VERSION 5.7 ;
  NOWIREEXTENSIONATPIN ON ;
  DIVIDERCHAR "/" ;
  BUSBITCHARS "[]" ;
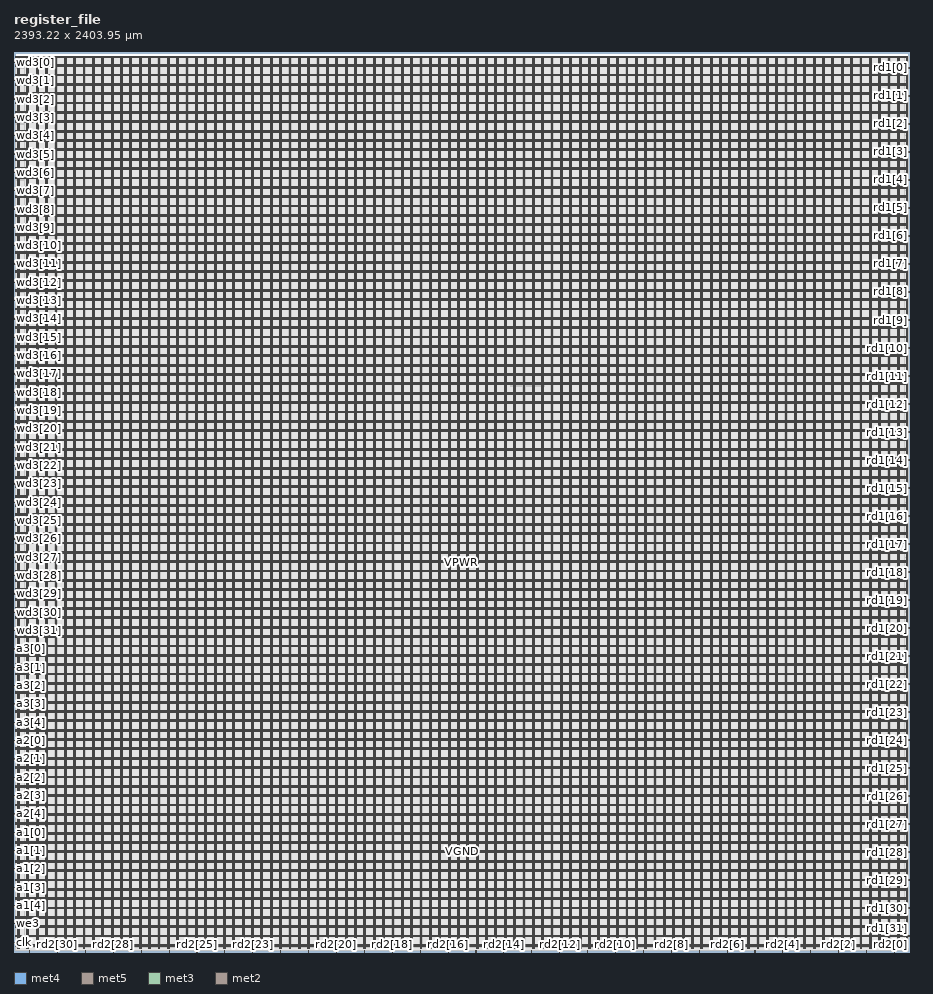
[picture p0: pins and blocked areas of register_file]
MACRO register_file
  CLASS BLOCK ;
  FOREIGN register_file ;
  ORIGIN 0.000 0.000 ;
  SIZE 2393.225 BY 2403.945 ;
  PIN VGND
    DIRECTION INOUT ;
    USE GROUND ;
    PORT
      LAYER met4 ;
        RECT 13.020 10.640 14.620 2391.120 ;
    END
    PORT
      LAYER met4 ;
        RECT 38.020 10.640 39.620 2391.120 ;
    END
    PORT
      LAYER met4 ;
        RECT 63.020 10.640 64.620 2391.120 ;
    END
    PORT
      LAYER met4 ;
        RECT 88.020 10.640 89.620 2391.120 ;
    END
    PORT
      LAYER met4 ;
        RECT 113.020 10.640 114.620 2391.120 ;
    END
    PORT
      LAYER met4 ;
        RECT 138.020 10.640 139.620 2391.120 ;
    END
    PORT
      LAYER met4 ;
        RECT 163.020 10.640 164.620 2391.120 ;
    END
    PORT
      LAYER met4 ;
        RECT 188.020 10.640 189.620 2391.120 ;
    END
    PORT
      LAYER met4 ;
        RECT 213.020 10.640 214.620 2391.120 ;
    END
    PORT
      LAYER met4 ;
        RECT 238.020 10.640 239.620 2391.120 ;
    END
    PORT
      LAYER met4 ;
        RECT 263.020 10.640 264.620 2391.120 ;
    END
    PORT
      LAYER met4 ;
        RECT 288.020 10.640 289.620 2391.120 ;
    END
    PORT
      LAYER met4 ;
        RECT 313.020 10.640 314.620 2391.120 ;
    END
    PORT
      LAYER met4 ;
        RECT 338.020 10.640 339.620 2391.120 ;
    END
    PORT
      LAYER met4 ;
        RECT 363.020 10.640 364.620 2391.120 ;
    END
    PORT
      LAYER met4 ;
        RECT 388.020 10.640 389.620 2391.120 ;
    END
    PORT
      LAYER met4 ;
        RECT 413.020 10.640 414.620 2391.120 ;
    END
    PORT
      LAYER met4 ;
        RECT 438.020 10.640 439.620 2391.120 ;
    END
    PORT
      LAYER met4 ;
        RECT 463.020 10.640 464.620 2391.120 ;
    END
    PORT
      LAYER met4 ;
        RECT 488.020 10.640 489.620 2391.120 ;
    END
    PORT
      LAYER met4 ;
        RECT 513.020 10.640 514.620 2391.120 ;
    END
    PORT
      LAYER met4 ;
        RECT 538.020 10.640 539.620 2391.120 ;
    END
    PORT
      LAYER met4 ;
        RECT 563.020 10.640 564.620 2391.120 ;
    END
    PORT
      LAYER met4 ;
        RECT 588.020 10.640 589.620 2391.120 ;
    END
    PORT
      LAYER met4 ;
        RECT 613.020 10.640 614.620 2391.120 ;
    END
    PORT
      LAYER met4 ;
        RECT 638.020 10.640 639.620 2391.120 ;
    END
    PORT
      LAYER met4 ;
        RECT 663.020 10.640 664.620 2391.120 ;
    END
    PORT
      LAYER met4 ;
        RECT 688.020 10.640 689.620 2391.120 ;
    END
    PORT
      LAYER met4 ;
        RECT 713.020 10.640 714.620 2391.120 ;
    END
    PORT
      LAYER met4 ;
        RECT 738.020 10.640 739.620 2391.120 ;
    END
    PORT
      LAYER met4 ;
        RECT 763.020 10.640 764.620 2391.120 ;
    END
    PORT
      LAYER met4 ;
        RECT 788.020 10.640 789.620 2391.120 ;
    END
    PORT
      LAYER met4 ;
        RECT 813.020 10.640 814.620 2391.120 ;
    END
    PORT
      LAYER met4 ;
        RECT 838.020 10.640 839.620 2391.120 ;
    END
    PORT
      LAYER met4 ;
        RECT 863.020 10.640 864.620 2391.120 ;
    END
    PORT
      LAYER met4 ;
        RECT 888.020 10.640 889.620 2391.120 ;
    END
    PORT
      LAYER met4 ;
        RECT 913.020 10.640 914.620 2391.120 ;
    END
    PORT
      LAYER met4 ;
        RECT 938.020 10.640 939.620 2391.120 ;
    END
    PORT
      LAYER met4 ;
        RECT 963.020 10.640 964.620 2391.120 ;
    END
    PORT
      LAYER met4 ;
        RECT 988.020 10.640 989.620 2391.120 ;
    END
    PORT
      LAYER met4 ;
        RECT 1013.020 10.640 1014.620 2391.120 ;
    END
    PORT
      LAYER met4 ;
        RECT 1038.020 10.640 1039.620 2391.120 ;
    END
    PORT
      LAYER met4 ;
        RECT 1063.020 10.640 1064.620 2391.120 ;
    END
    PORT
      LAYER met4 ;
        RECT 1088.020 10.640 1089.620 2391.120 ;
    END
    PORT
      LAYER met4 ;
        RECT 1113.020 10.640 1114.620 2391.120 ;
    END
    PORT
      LAYER met4 ;
        RECT 1138.020 10.640 1139.620 2391.120 ;
    END
    PORT
      LAYER met4 ;
        RECT 1163.020 10.640 1164.620 2391.120 ;
    END
    PORT
      LAYER met4 ;
        RECT 1188.020 10.640 1189.620 2391.120 ;
    END
    PORT
      LAYER met4 ;
        RECT 1213.020 10.640 1214.620 2391.120 ;
    END
    PORT
      LAYER met4 ;
        RECT 1238.020 10.640 1239.620 2391.120 ;
    END
    PORT
      LAYER met4 ;
        RECT 1263.020 10.640 1264.620 2391.120 ;
    END
    PORT
      LAYER met4 ;
        RECT 1288.020 10.640 1289.620 2391.120 ;
    END
    PORT
      LAYER met4 ;
        RECT 1313.020 10.640 1314.620 2391.120 ;
    END
    PORT
      LAYER met4 ;
        RECT 1338.020 10.640 1339.620 2391.120 ;
    END
    PORT
      LAYER met4 ;
        RECT 1363.020 10.640 1364.620 2391.120 ;
    END
    PORT
      LAYER met4 ;
        RECT 1388.020 10.640 1389.620 2391.120 ;
    END
    PORT
      LAYER met4 ;
        RECT 1413.020 10.640 1414.620 2391.120 ;
    END
    PORT
      LAYER met4 ;
        RECT 1438.020 10.640 1439.620 2391.120 ;
    END
    PORT
      LAYER met4 ;
        RECT 1463.020 10.640 1464.620 2391.120 ;
    END
    PORT
      LAYER met4 ;
        RECT 1488.020 10.640 1489.620 2391.120 ;
    END
    PORT
      LAYER met4 ;
        RECT 1513.020 10.640 1514.620 2391.120 ;
    END
    PORT
      LAYER met4 ;
        RECT 1538.020 10.640 1539.620 2391.120 ;
    END
    PORT
      LAYER met4 ;
        RECT 1563.020 10.640 1564.620 2391.120 ;
    END
    PORT
      LAYER met4 ;
        RECT 1588.020 10.640 1589.620 2391.120 ;
    END
    PORT
      LAYER met4 ;
        RECT 1613.020 10.640 1614.620 2391.120 ;
    END
    PORT
      LAYER met4 ;
        RECT 1638.020 10.640 1639.620 2391.120 ;
    END
    PORT
      LAYER met4 ;
        RECT 1663.020 10.640 1664.620 2391.120 ;
    END
    PORT
      LAYER met4 ;
        RECT 1688.020 10.640 1689.620 2391.120 ;
    END
    PORT
      LAYER met4 ;
        RECT 1713.020 10.640 1714.620 2391.120 ;
    END
    PORT
      LAYER met4 ;
        RECT 1738.020 10.640 1739.620 2391.120 ;
    END
    PORT
      LAYER met4 ;
        RECT 1763.020 10.640 1764.620 2391.120 ;
    END
    PORT
      LAYER met4 ;
        RECT 1788.020 10.640 1789.620 2391.120 ;
    END
    PORT
      LAYER met4 ;
        RECT 1813.020 10.640 1814.620 2391.120 ;
    END
    PORT
      LAYER met4 ;
        RECT 1838.020 10.640 1839.620 2391.120 ;
    END
    PORT
      LAYER met4 ;
        RECT 1863.020 10.640 1864.620 2391.120 ;
    END
    PORT
      LAYER met4 ;
        RECT 1888.020 10.640 1889.620 2391.120 ;
    END
    PORT
      LAYER met4 ;
        RECT 1913.020 10.640 1914.620 2391.120 ;
    END
    PORT
      LAYER met4 ;
        RECT 1938.020 10.640 1939.620 2391.120 ;
    END
    PORT
      LAYER met4 ;
        RECT 1963.020 10.640 1964.620 2391.120 ;
    END
    PORT
      LAYER met4 ;
        RECT 1988.020 10.640 1989.620 2391.120 ;
    END
    PORT
      LAYER met4 ;
        RECT 2013.020 10.640 2014.620 2391.120 ;
    END
    PORT
      LAYER met4 ;
        RECT 2038.020 10.640 2039.620 2391.120 ;
    END
    PORT
      LAYER met4 ;
        RECT 2063.020 10.640 2064.620 2391.120 ;
    END
    PORT
      LAYER met4 ;
        RECT 2088.020 10.640 2089.620 2391.120 ;
    END
    PORT
      LAYER met4 ;
        RECT 2113.020 10.640 2114.620 2391.120 ;
    END
    PORT
      LAYER met4 ;
        RECT 2138.020 10.640 2139.620 2391.120 ;
    END
    PORT
      LAYER met4 ;
        RECT 2163.020 10.640 2164.620 2391.120 ;
    END
    PORT
      LAYER met4 ;
        RECT 2188.020 10.640 2189.620 2391.120 ;
    END
    PORT
      LAYER met4 ;
        RECT 2213.020 10.640 2214.620 2391.120 ;
    END
    PORT
      LAYER met4 ;
        RECT 2238.020 10.640 2239.620 2391.120 ;
    END
    PORT
      LAYER met4 ;
        RECT 2263.020 10.640 2264.620 2391.120 ;
    END
    PORT
      LAYER met4 ;
        RECT 2288.020 10.640 2289.620 2391.120 ;
    END
    PORT
      LAYER met4 ;
        RECT 2313.020 10.640 2314.620 2391.120 ;
    END
    PORT
      LAYER met4 ;
        RECT 2338.020 10.640 2339.620 2391.120 ;
    END
    PORT
      LAYER met4 ;
        RECT 2363.020 10.640 2364.620 2391.120 ;
    END
    PORT
      LAYER met5 ;
        RECT 5.280 18.380 2387.640 19.980 ;
    END
    PORT
      LAYER met5 ;
        RECT 5.280 43.380 2387.640 44.980 ;
    END
    PORT
      LAYER met5 ;
        RECT 5.280 68.380 2387.640 69.980 ;
    END
    PORT
      LAYER met5 ;
        RECT 5.280 93.380 2387.640 94.980 ;
    END
    PORT
      LAYER met5 ;
        RECT 5.280 118.380 2387.640 119.980 ;
    END
    PORT
      LAYER met5 ;
        RECT 5.280 143.380 2387.640 144.980 ;
    END
    PORT
      LAYER met5 ;
        RECT 5.280 168.380 2387.640 169.980 ;
    END
    PORT
      LAYER met5 ;
        RECT 5.280 193.380 2387.640 194.980 ;
    END
    PORT
      LAYER met5 ;
        RECT 5.280 218.380 2387.640 219.980 ;
    END
    PORT
      LAYER met5 ;
        RECT 5.280 243.380 2387.640 244.980 ;
    END
    PORT
      LAYER met5 ;
        RECT 5.280 268.380 2387.640 269.980 ;
    END
    PORT
      LAYER met5 ;
        RECT 5.280 293.380 2387.640 294.980 ;
    END
    PORT
      LAYER met5 ;
        RECT 5.280 318.380 2387.640 319.980 ;
    END
    PORT
      LAYER met5 ;
        RECT 5.280 343.380 2387.640 344.980 ;
    END
    PORT
      LAYER met5 ;
        RECT 5.280 368.380 2387.640 369.980 ;
    END
    PORT
      LAYER met5 ;
        RECT 5.280 393.380 2387.640 394.980 ;
    END
    PORT
      LAYER met5 ;
        RECT 5.280 418.380 2387.640 419.980 ;
    END
    PORT
      LAYER met5 ;
        RECT 5.280 443.380 2387.640 444.980 ;
    END
    PORT
      LAYER met5 ;
        RECT 5.280 468.380 2387.640 469.980 ;
    END
    PORT
      LAYER met5 ;
        RECT 5.280 493.380 2387.640 494.980 ;
    END
    PORT
      LAYER met5 ;
        RECT 5.280 518.380 2387.640 519.980 ;
    END
    PORT
      LAYER met5 ;
        RECT 5.280 543.380 2387.640 544.980 ;
    END
    PORT
      LAYER met5 ;
        RECT 5.280 568.380 2387.640 569.980 ;
    END
    PORT
      LAYER met5 ;
        RECT 5.280 593.380 2387.640 594.980 ;
    END
    PORT
      LAYER met5 ;
        RECT 5.280 618.380 2387.640 619.980 ;
    END
    PORT
      LAYER met5 ;
        RECT 5.280 643.380 2387.640 644.980 ;
    END
    PORT
      LAYER met5 ;
        RECT 5.280 668.380 2387.640 669.980 ;
    END
    PORT
      LAYER met5 ;
        RECT 5.280 693.380 2387.640 694.980 ;
    END
    PORT
      LAYER met5 ;
        RECT 5.280 718.380 2387.640 719.980 ;
    END
    PORT
      LAYER met5 ;
        RECT 5.280 743.380 2387.640 744.980 ;
    END
    PORT
      LAYER met5 ;
        RECT 5.280 768.380 2387.640 769.980 ;
    END
    PORT
      LAYER met5 ;
        RECT 5.280 793.380 2387.640 794.980 ;
    END
    PORT
      LAYER met5 ;
        RECT 5.280 818.380 2387.640 819.980 ;
    END
    PORT
      LAYER met5 ;
        RECT 5.280 843.380 2387.640 844.980 ;
    END
    PORT
      LAYER met5 ;
        RECT 5.280 868.380 2387.640 869.980 ;
    END
    PORT
      LAYER met5 ;
        RECT 5.280 893.380 2387.640 894.980 ;
    END
    PORT
      LAYER met5 ;
        RECT 5.280 918.380 2387.640 919.980 ;
    END
    PORT
      LAYER met5 ;
        RECT 5.280 943.380 2387.640 944.980 ;
    END
    PORT
      LAYER met5 ;
        RECT 5.280 968.380 2387.640 969.980 ;
    END
    PORT
      LAYER met5 ;
        RECT 5.280 993.380 2387.640 994.980 ;
    END
    PORT
      LAYER met5 ;
        RECT 5.280 1018.380 2387.640 1019.980 ;
    END
    PORT
      LAYER met5 ;
        RECT 5.280 1043.380 2387.640 1044.980 ;
    END
    PORT
      LAYER met5 ;
        RECT 5.280 1068.380 2387.640 1069.980 ;
    END
    PORT
      LAYER met5 ;
        RECT 5.280 1093.380 2387.640 1094.980 ;
    END
    PORT
      LAYER met5 ;
        RECT 5.280 1118.380 2387.640 1119.980 ;
    END
    PORT
      LAYER met5 ;
        RECT 5.280 1143.380 2387.640 1144.980 ;
    END
    PORT
      LAYER met5 ;
        RECT 5.280 1168.380 2387.640 1169.980 ;
    END
    PORT
      LAYER met5 ;
        RECT 5.280 1193.380 2387.640 1194.980 ;
    END
    PORT
      LAYER met5 ;
        RECT 5.280 1218.380 2387.640 1219.980 ;
    END
    PORT
      LAYER met5 ;
        RECT 5.280 1243.380 2387.640 1244.980 ;
    END
    PORT
      LAYER met5 ;
        RECT 5.280 1268.380 2387.640 1269.980 ;
    END
    PORT
      LAYER met5 ;
        RECT 5.280 1293.380 2387.640 1294.980 ;
    END
    PORT
      LAYER met5 ;
        RECT 5.280 1318.380 2387.640 1319.980 ;
    END
    PORT
      LAYER met5 ;
        RECT 5.280 1343.380 2387.640 1344.980 ;
    END
    PORT
      LAYER met5 ;
        RECT 5.280 1368.380 2387.640 1369.980 ;
    END
    PORT
      LAYER met5 ;
        RECT 5.280 1393.380 2387.640 1394.980 ;
    END
    PORT
      LAYER met5 ;
        RECT 5.280 1418.380 2387.640 1419.980 ;
    END
    PORT
      LAYER met5 ;
        RECT 5.280 1443.380 2387.640 1444.980 ;
    END
    PORT
      LAYER met5 ;
        RECT 5.280 1468.380 2387.640 1469.980 ;
    END
    PORT
      LAYER met5 ;
        RECT 5.280 1493.380 2387.640 1494.980 ;
    END
    PORT
      LAYER met5 ;
        RECT 5.280 1518.380 2387.640 1519.980 ;
    END
    PORT
      LAYER met5 ;
        RECT 5.280 1543.380 2387.640 1544.980 ;
    END
    PORT
      LAYER met5 ;
        RECT 5.280 1568.380 2387.640 1569.980 ;
    END
    PORT
      LAYER met5 ;
        RECT 5.280 1593.380 2387.640 1594.980 ;
    END
    PORT
      LAYER met5 ;
        RECT 5.280 1618.380 2387.640 1619.980 ;
    END
    PORT
      LAYER met5 ;
        RECT 5.280 1643.380 2387.640 1644.980 ;
    END
    PORT
      LAYER met5 ;
        RECT 5.280 1668.380 2387.640 1669.980 ;
    END
    PORT
      LAYER met5 ;
        RECT 5.280 1693.380 2387.640 1694.980 ;
    END
    PORT
      LAYER met5 ;
        RECT 5.280 1718.380 2387.640 1719.980 ;
    END
    PORT
      LAYER met5 ;
        RECT 5.280 1743.380 2387.640 1744.980 ;
    END
    PORT
      LAYER met5 ;
        RECT 5.280 1768.380 2387.640 1769.980 ;
    END
    PORT
      LAYER met5 ;
        RECT 5.280 1793.380 2387.640 1794.980 ;
    END
    PORT
      LAYER met5 ;
        RECT 5.280 1818.380 2387.640 1819.980 ;
    END
    PORT
      LAYER met5 ;
        RECT 5.280 1843.380 2387.640 1844.980 ;
    END
    PORT
      LAYER met5 ;
        RECT 5.280 1868.380 2387.640 1869.980 ;
    END
    PORT
      LAYER met5 ;
        RECT 5.280 1893.380 2387.640 1894.980 ;
    END
    PORT
      LAYER met5 ;
        RECT 5.280 1918.380 2387.640 1919.980 ;
    END
    PORT
      LAYER met5 ;
        RECT 5.280 1943.380 2387.640 1944.980 ;
    END
    PORT
      LAYER met5 ;
        RECT 5.280 1968.380 2387.640 1969.980 ;
    END
    PORT
      LAYER met5 ;
        RECT 5.280 1993.380 2387.640 1994.980 ;
    END
    PORT
      LAYER met5 ;
        RECT 5.280 2018.380 2387.640 2019.980 ;
    END
    PORT
      LAYER met5 ;
        RECT 5.280 2043.380 2387.640 2044.980 ;
    END
    PORT
      LAYER met5 ;
        RECT 5.280 2068.380 2387.640 2069.980 ;
    END
    PORT
      LAYER met5 ;
        RECT 5.280 2093.380 2387.640 2094.980 ;
    END
    PORT
      LAYER met5 ;
        RECT 5.280 2118.380 2387.640 2119.980 ;
    END
    PORT
      LAYER met5 ;
        RECT 5.280 2143.380 2387.640 2144.980 ;
    END
    PORT
      LAYER met5 ;
        RECT 5.280 2168.380 2387.640 2169.980 ;
    END
    PORT
      LAYER met5 ;
        RECT 5.280 2193.380 2387.640 2194.980 ;
    END
    PORT
      LAYER met5 ;
        RECT 5.280 2218.380 2387.640 2219.980 ;
    END
    PORT
      LAYER met5 ;
        RECT 5.280 2243.380 2387.640 2244.980 ;
    END
    PORT
      LAYER met5 ;
        RECT 5.280 2268.380 2387.640 2269.980 ;
    END
    PORT
      LAYER met5 ;
        RECT 5.280 2293.380 2387.640 2294.980 ;
    END
    PORT
      LAYER met5 ;
        RECT 5.280 2318.380 2387.640 2319.980 ;
    END
    PORT
      LAYER met5 ;
        RECT 5.280 2343.380 2387.640 2344.980 ;
    END
    PORT
      LAYER met5 ;
        RECT 5.280 2368.380 2387.640 2369.980 ;
    END
  END VGND
  PIN VPWR
    DIRECTION INOUT ;
    USE POWER ;
    PORT
      LAYER met4 ;
        RECT 9.720 10.640 11.320 2391.680 ;
    END
    PORT
      LAYER met4 ;
        RECT 34.720 10.640 36.320 2391.680 ;
    END
    PORT
      LAYER met4 ;
        RECT 59.720 10.640 61.320 2391.680 ;
    END
    PORT
      LAYER met4 ;
        RECT 84.720 10.640 86.320 2391.680 ;
    END
    PORT
      LAYER met4 ;
        RECT 109.720 10.640 111.320 2391.680 ;
    END
    PORT
      LAYER met4 ;
        RECT 134.720 10.640 136.320 2391.680 ;
    END
    PORT
      LAYER met4 ;
        RECT 159.720 10.640 161.320 2391.680 ;
    END
    PORT
      LAYER met4 ;
        RECT 184.720 10.640 186.320 2391.680 ;
    END
    PORT
      LAYER met4 ;
        RECT 209.720 10.640 211.320 2391.680 ;
    END
    PORT
      LAYER met4 ;
        RECT 234.720 10.640 236.320 2391.680 ;
    END
    PORT
      LAYER met4 ;
        RECT 259.720 10.640 261.320 2391.680 ;
    END
    PORT
      LAYER met4 ;
        RECT 284.720 10.640 286.320 2391.680 ;
    END
    PORT
      LAYER met4 ;
        RECT 309.720 10.640 311.320 2391.680 ;
    END
    PORT
      LAYER met4 ;
        RECT 334.720 10.640 336.320 2391.680 ;
    END
    PORT
      LAYER met4 ;
        RECT 359.720 10.640 361.320 2391.680 ;
    END
    PORT
      LAYER met4 ;
        RECT 384.720 10.640 386.320 2391.680 ;
    END
    PORT
      LAYER met4 ;
        RECT 409.720 10.640 411.320 2391.680 ;
    END
    PORT
      LAYER met4 ;
        RECT 434.720 10.640 436.320 2391.680 ;
    END
    PORT
      LAYER met4 ;
        RECT 459.720 10.640 461.320 2391.680 ;
    END
    PORT
      LAYER met4 ;
        RECT 484.720 10.640 486.320 2391.680 ;
    END
    PORT
      LAYER met4 ;
        RECT 509.720 10.640 511.320 2391.680 ;
    END
    PORT
      LAYER met4 ;
        RECT 534.720 10.640 536.320 2391.680 ;
    END
    PORT
      LAYER met4 ;
        RECT 559.720 10.640 561.320 2391.680 ;
    END
    PORT
      LAYER met4 ;
        RECT 584.720 10.640 586.320 2391.680 ;
    END
    PORT
      LAYER met4 ;
        RECT 609.720 10.640 611.320 2391.680 ;
    END
    PORT
      LAYER met4 ;
        RECT 634.720 10.640 636.320 2391.680 ;
    END
    PORT
      LAYER met4 ;
        RECT 659.720 10.640 661.320 2391.680 ;
    END
    PORT
      LAYER met4 ;
        RECT 684.720 10.640 686.320 2391.680 ;
    END
    PORT
      LAYER met4 ;
        RECT 709.720 10.640 711.320 2391.680 ;
    END
    PORT
      LAYER met4 ;
        RECT 734.720 10.640 736.320 2391.680 ;
    END
    PORT
      LAYER met4 ;
        RECT 759.720 10.640 761.320 2391.680 ;
    END
    PORT
      LAYER met4 ;
        RECT 784.720 10.640 786.320 2391.680 ;
    END
    PORT
      LAYER met4 ;
        RECT 809.720 10.640 811.320 2391.680 ;
    END
    PORT
      LAYER met4 ;
        RECT 834.720 10.640 836.320 2391.680 ;
    END
    PORT
      LAYER met4 ;
        RECT 859.720 10.640 861.320 2391.680 ;
    END
    PORT
      LAYER met4 ;
        RECT 884.720 10.640 886.320 2391.680 ;
    END
    PORT
      LAYER met4 ;
        RECT 909.720 10.640 911.320 2391.680 ;
    END
    PORT
      LAYER met4 ;
        RECT 934.720 10.640 936.320 2391.680 ;
    END
    PORT
      LAYER met4 ;
        RECT 959.720 10.640 961.320 2391.680 ;
    END
    PORT
      LAYER met4 ;
        RECT 984.720 10.640 986.320 2391.680 ;
    END
    PORT
      LAYER met4 ;
        RECT 1009.720 10.640 1011.320 2391.680 ;
    END
    PORT
      LAYER met4 ;
        RECT 1034.720 10.640 1036.320 2391.680 ;
    END
    PORT
      LAYER met4 ;
        RECT 1059.720 10.640 1061.320 2391.680 ;
    END
    PORT
      LAYER met4 ;
        RECT 1084.720 10.640 1086.320 2391.680 ;
    END
    PORT
      LAYER met4 ;
        RECT 1109.720 10.640 1111.320 2391.680 ;
    END
    PORT
      LAYER met4 ;
        RECT 1134.720 10.640 1136.320 2391.680 ;
    END
    PORT
      LAYER met4 ;
        RECT 1159.720 10.640 1161.320 2391.680 ;
    END
    PORT
      LAYER met4 ;
        RECT 1184.720 10.640 1186.320 2391.680 ;
    END
    PORT
      LAYER met4 ;
        RECT 1209.720 10.640 1211.320 2391.680 ;
    END
    PORT
      LAYER met4 ;
        RECT 1234.720 10.640 1236.320 2391.680 ;
    END
    PORT
      LAYER met4 ;
        RECT 1259.720 10.640 1261.320 2391.680 ;
    END
    PORT
      LAYER met4 ;
        RECT 1284.720 10.640 1286.320 2391.680 ;
    END
    PORT
      LAYER met4 ;
        RECT 1309.720 10.640 1311.320 2391.680 ;
    END
    PORT
      LAYER met4 ;
        RECT 1334.720 10.640 1336.320 2391.680 ;
    END
    PORT
      LAYER met4 ;
        RECT 1359.720 10.640 1361.320 2391.680 ;
    END
    PORT
      LAYER met4 ;
        RECT 1384.720 10.640 1386.320 2391.680 ;
    END
    PORT
      LAYER met4 ;
        RECT 1409.720 10.640 1411.320 2391.680 ;
    END
    PORT
      LAYER met4 ;
        RECT 1434.720 10.640 1436.320 2391.680 ;
    END
    PORT
      LAYER met4 ;
        RECT 1459.720 10.640 1461.320 2391.680 ;
    END
    PORT
      LAYER met4 ;
        RECT 1484.720 10.640 1486.320 2391.680 ;
    END
    PORT
      LAYER met4 ;
        RECT 1509.720 10.640 1511.320 2391.680 ;
    END
    PORT
      LAYER met4 ;
        RECT 1534.720 10.640 1536.320 2391.680 ;
    END
    PORT
      LAYER met4 ;
        RECT 1559.720 10.640 1561.320 2391.680 ;
    END
    PORT
      LAYER met4 ;
        RECT 1584.720 10.640 1586.320 2391.680 ;
    END
    PORT
      LAYER met4 ;
        RECT 1609.720 10.640 1611.320 2391.680 ;
    END
    PORT
      LAYER met4 ;
        RECT 1634.720 10.640 1636.320 2391.680 ;
    END
    PORT
      LAYER met4 ;
        RECT 1659.720 10.640 1661.320 2391.680 ;
    END
    PORT
      LAYER met4 ;
        RECT 1684.720 10.640 1686.320 2391.680 ;
    END
    PORT
      LAYER met4 ;
        RECT 1709.720 10.640 1711.320 2391.680 ;
    END
    PORT
      LAYER met4 ;
        RECT 1734.720 10.640 1736.320 2391.680 ;
    END
    PORT
      LAYER met4 ;
        RECT 1759.720 10.640 1761.320 2391.680 ;
    END
    PORT
      LAYER met4 ;
        RECT 1784.720 10.640 1786.320 2391.680 ;
    END
    PORT
      LAYER met4 ;
        RECT 1809.720 10.640 1811.320 2391.680 ;
    END
    PORT
      LAYER met4 ;
        RECT 1834.720 10.640 1836.320 2391.680 ;
    END
    PORT
      LAYER met4 ;
        RECT 1859.720 10.640 1861.320 2391.680 ;
    END
    PORT
      LAYER met4 ;
        RECT 1884.720 10.640 1886.320 2391.680 ;
    END
    PORT
      LAYER met4 ;
        RECT 1909.720 10.640 1911.320 2391.680 ;
    END
    PORT
      LAYER met4 ;
        RECT 1934.720 10.640 1936.320 2391.680 ;
    END
    PORT
      LAYER met4 ;
        RECT 1959.720 10.640 1961.320 2391.680 ;
    END
    PORT
      LAYER met4 ;
        RECT 1984.720 10.640 1986.320 2391.680 ;
    END
    PORT
      LAYER met4 ;
        RECT 2009.720 10.640 2011.320 2391.680 ;
    END
    PORT
      LAYER met4 ;
        RECT 2034.720 10.640 2036.320 2391.680 ;
    END
    PORT
      LAYER met4 ;
        RECT 2059.720 10.640 2061.320 2391.680 ;
    END
    PORT
      LAYER met4 ;
        RECT 2084.720 10.640 2086.320 2391.680 ;
    END
    PORT
      LAYER met4 ;
        RECT 2109.720 10.640 2111.320 2391.680 ;
    END
    PORT
      LAYER met4 ;
        RECT 2134.720 10.640 2136.320 2391.680 ;
    END
    PORT
      LAYER met4 ;
        RECT 2159.720 10.640 2161.320 2391.680 ;
    END
    PORT
      LAYER met4 ;
        RECT 2184.720 10.640 2186.320 2391.680 ;
    END
    PORT
      LAYER met4 ;
        RECT 2209.720 10.640 2211.320 2391.680 ;
    END
    PORT
      LAYER met4 ;
        RECT 2234.720 10.640 2236.320 2391.680 ;
    END
    PORT
      LAYER met4 ;
        RECT 2259.720 10.640 2261.320 2391.680 ;
    END
    PORT
      LAYER met4 ;
        RECT 2284.720 10.640 2286.320 2391.680 ;
    END
    PORT
      LAYER met4 ;
        RECT 2309.720 10.640 2311.320 2391.680 ;
    END
    PORT
      LAYER met4 ;
        RECT 2334.720 10.640 2336.320 2391.680 ;
    END
    PORT
      LAYER met4 ;
        RECT 2359.720 10.640 2361.320 2391.680 ;
    END
    PORT
      LAYER met4 ;
        RECT 2384.720 10.640 2386.320 2391.680 ;
    END
    PORT
      LAYER met5 ;
        RECT 5.280 15.080 2387.640 16.680 ;
    END
    PORT
      LAYER met5 ;
        RECT 5.280 40.080 2387.640 41.680 ;
    END
    PORT
      LAYER met5 ;
        RECT 5.280 65.080 2387.640 66.680 ;
    END
    PORT
      LAYER met5 ;
        RECT 5.280 90.080 2387.640 91.680 ;
    END
    PORT
      LAYER met5 ;
        RECT 5.280 115.080 2387.640 116.680 ;
    END
    PORT
      LAYER met5 ;
        RECT 5.280 140.080 2387.640 141.680 ;
    END
    PORT
      LAYER met5 ;
        RECT 5.280 165.080 2387.640 166.680 ;
    END
    PORT
      LAYER met5 ;
        RECT 5.280 190.080 2387.640 191.680 ;
    END
    PORT
      LAYER met5 ;
        RECT 5.280 215.080 2387.640 216.680 ;
    END
    PORT
      LAYER met5 ;
        RECT 5.280 240.080 2387.640 241.680 ;
    END
    PORT
      LAYER met5 ;
        RECT 5.280 265.080 2387.640 266.680 ;
    END
    PORT
      LAYER met5 ;
        RECT 5.280 290.080 2387.640 291.680 ;
    END
    PORT
      LAYER met5 ;
        RECT 5.280 315.080 2387.640 316.680 ;
    END
    PORT
      LAYER met5 ;
        RECT 5.280 340.080 2387.640 341.680 ;
    END
    PORT
      LAYER met5 ;
        RECT 5.280 365.080 2387.640 366.680 ;
    END
    PORT
      LAYER met5 ;
        RECT 5.280 390.080 2387.640 391.680 ;
    END
    PORT
      LAYER met5 ;
        RECT 5.280 415.080 2387.640 416.680 ;
    END
    PORT
      LAYER met5 ;
        RECT 5.280 440.080 2387.640 441.680 ;
    END
    PORT
      LAYER met5 ;
        RECT 5.280 465.080 2387.640 466.680 ;
    END
    PORT
      LAYER met5 ;
        RECT 5.280 490.080 2387.640 491.680 ;
    END
    PORT
      LAYER met5 ;
        RECT 5.280 515.080 2387.640 516.680 ;
    END
    PORT
      LAYER met5 ;
        RECT 5.280 540.080 2387.640 541.680 ;
    END
    PORT
      LAYER met5 ;
        RECT 5.280 565.080 2387.640 566.680 ;
    END
    PORT
      LAYER met5 ;
        RECT 5.280 590.080 2387.640 591.680 ;
    END
    PORT
      LAYER met5 ;
        RECT 5.280 615.080 2387.640 616.680 ;
    END
    PORT
      LAYER met5 ;
        RECT 5.280 640.080 2387.640 641.680 ;
    END
    PORT
      LAYER met5 ;
        RECT 5.280 665.080 2387.640 666.680 ;
    END
    PORT
      LAYER met5 ;
        RECT 5.280 690.080 2387.640 691.680 ;
    END
    PORT
      LAYER met5 ;
        RECT 5.280 715.080 2387.640 716.680 ;
    END
    PORT
      LAYER met5 ;
        RECT 5.280 740.080 2387.640 741.680 ;
    END
    PORT
      LAYER met5 ;
        RECT 5.280 765.080 2387.640 766.680 ;
    END
    PORT
      LAYER met5 ;
        RECT 5.280 790.080 2387.640 791.680 ;
    END
    PORT
      LAYER met5 ;
        RECT 5.280 815.080 2387.640 816.680 ;
    END
    PORT
      LAYER met5 ;
        RECT 5.280 840.080 2387.640 841.680 ;
    END
    PORT
      LAYER met5 ;
        RECT 5.280 865.080 2387.640 866.680 ;
    END
    PORT
      LAYER met5 ;
        RECT 5.280 890.080 2387.640 891.680 ;
    END
    PORT
      LAYER met5 ;
        RECT 5.280 915.080 2387.640 916.680 ;
    END
    PORT
      LAYER met5 ;
        RECT 5.280 940.080 2387.640 941.680 ;
    END
    PORT
      LAYER met5 ;
        RECT 5.280 965.080 2387.640 966.680 ;
    END
    PORT
      LAYER met5 ;
        RECT 5.280 990.080 2387.640 991.680 ;
    END
    PORT
      LAYER met5 ;
        RECT 5.280 1015.080 2387.640 1016.680 ;
    END
    PORT
      LAYER met5 ;
        RECT 5.280 1040.080 2387.640 1041.680 ;
    END
    PORT
      LAYER met5 ;
        RECT 5.280 1065.080 2387.640 1066.680 ;
    END
    PORT
      LAYER met5 ;
        RECT 5.280 1090.080 2387.640 1091.680 ;
    END
    PORT
      LAYER met5 ;
        RECT 5.280 1115.080 2387.640 1116.680 ;
    END
    PORT
      LAYER met5 ;
        RECT 5.280 1140.080 2387.640 1141.680 ;
    END
    PORT
      LAYER met5 ;
        RECT 5.280 1165.080 2387.640 1166.680 ;
    END
    PORT
      LAYER met5 ;
        RECT 5.280 1190.080 2387.640 1191.680 ;
    END
    PORT
      LAYER met5 ;
        RECT 5.280 1215.080 2387.640 1216.680 ;
    END
    PORT
      LAYER met5 ;
        RECT 5.280 1240.080 2387.640 1241.680 ;
    END
    PORT
      LAYER met5 ;
        RECT 5.280 1265.080 2387.640 1266.680 ;
    END
    PORT
      LAYER met5 ;
        RECT 5.280 1290.080 2387.640 1291.680 ;
    END
    PORT
      LAYER met5 ;
        RECT 5.280 1315.080 2387.640 1316.680 ;
    END
    PORT
      LAYER met5 ;
        RECT 5.280 1340.080 2387.640 1341.680 ;
    END
    PORT
      LAYER met5 ;
        RECT 5.280 1365.080 2387.640 1366.680 ;
    END
    PORT
      LAYER met5 ;
        RECT 5.280 1390.080 2387.640 1391.680 ;
    END
    PORT
      LAYER met5 ;
        RECT 5.280 1415.080 2387.640 1416.680 ;
    END
    PORT
      LAYER met5 ;
        RECT 5.280 1440.080 2387.640 1441.680 ;
    END
    PORT
      LAYER met5 ;
        RECT 5.280 1465.080 2387.640 1466.680 ;
    END
    PORT
      LAYER met5 ;
        RECT 5.280 1490.080 2387.640 1491.680 ;
    END
    PORT
      LAYER met5 ;
        RECT 5.280 1515.080 2387.640 1516.680 ;
    END
    PORT
      LAYER met5 ;
        RECT 5.280 1540.080 2387.640 1541.680 ;
    END
    PORT
      LAYER met5 ;
        RECT 5.280 1565.080 2387.640 1566.680 ;
    END
    PORT
      LAYER met5 ;
        RECT 5.280 1590.080 2387.640 1591.680 ;
    END
    PORT
      LAYER met5 ;
        RECT 5.280 1615.080 2387.640 1616.680 ;
    END
    PORT
      LAYER met5 ;
        RECT 5.280 1640.080 2387.640 1641.680 ;
    END
    PORT
      LAYER met5 ;
        RECT 5.280 1665.080 2387.640 1666.680 ;
    END
    PORT
      LAYER met5 ;
        RECT 5.280 1690.080 2387.640 1691.680 ;
    END
    PORT
      LAYER met5 ;
        RECT 5.280 1715.080 2387.640 1716.680 ;
    END
    PORT
      LAYER met5 ;
        RECT 5.280 1740.080 2387.640 1741.680 ;
    END
    PORT
      LAYER met5 ;
        RECT 5.280 1765.080 2387.640 1766.680 ;
    END
    PORT
      LAYER met5 ;
        RECT 5.280 1790.080 2387.640 1791.680 ;
    END
    PORT
      LAYER met5 ;
        RECT 5.280 1815.080 2387.640 1816.680 ;
    END
    PORT
      LAYER met5 ;
        RECT 5.280 1840.080 2387.640 1841.680 ;
    END
    PORT
      LAYER met5 ;
        RECT 5.280 1865.080 2387.640 1866.680 ;
    END
    PORT
      LAYER met5 ;
        RECT 5.280 1890.080 2387.640 1891.680 ;
    END
    PORT
      LAYER met5 ;
        RECT 5.280 1915.080 2387.640 1916.680 ;
    END
    PORT
      LAYER met5 ;
        RECT 5.280 1940.080 2387.640 1941.680 ;
    END
    PORT
      LAYER met5 ;
        RECT 5.280 1965.080 2387.640 1966.680 ;
    END
    PORT
      LAYER met5 ;
        RECT 5.280 1990.080 2387.640 1991.680 ;
    END
    PORT
      LAYER met5 ;
        RECT 5.280 2015.080 2387.640 2016.680 ;
    END
    PORT
      LAYER met5 ;
        RECT 5.280 2040.080 2387.640 2041.680 ;
    END
    PORT
      LAYER met5 ;
        RECT 5.280 2065.080 2387.640 2066.680 ;
    END
    PORT
      LAYER met5 ;
        RECT 5.280 2090.080 2387.640 2091.680 ;
    END
    PORT
      LAYER met5 ;
        RECT 5.280 2115.080 2387.640 2116.680 ;
    END
    PORT
      LAYER met5 ;
        RECT 5.280 2140.080 2387.640 2141.680 ;
    END
    PORT
      LAYER met5 ;
        RECT 5.280 2165.080 2387.640 2166.680 ;
    END
    PORT
      LAYER met5 ;
        RECT 5.280 2190.080 2387.640 2191.680 ;
    END
    PORT
      LAYER met5 ;
        RECT 5.280 2215.080 2387.640 2216.680 ;
    END
    PORT
      LAYER met5 ;
        RECT 5.280 2240.080 2387.640 2241.680 ;
    END
    PORT
      LAYER met5 ;
        RECT 5.280 2265.080 2387.640 2266.680 ;
    END
    PORT
      LAYER met5 ;
        RECT 5.280 2290.080 2387.640 2291.680 ;
    END
    PORT
      LAYER met5 ;
        RECT 5.280 2315.080 2387.640 2316.680 ;
    END
    PORT
      LAYER met5 ;
        RECT 5.280 2340.080 2387.640 2341.680 ;
    END
    PORT
      LAYER met5 ;
        RECT 5.280 2365.080 2387.640 2366.680 ;
    END
    PORT
      LAYER met5 ;
        RECT 5.280 2390.080 2387.640 2391.680 ;
    END
  END VPWR
  PIN a1[0]
    DIRECTION INPUT ;
    USE SIGNAL ;
    ANTENNAGATEAREA 0.852000 ;
    ANTENNADIFFAREA 2.173500 ;
    PORT
      LAYER met3 ;
        RECT 0.000 319.640 4.000 320.240 ;
    END
  END a1[0]
  PIN a1[1]
    DIRECTION INPUT ;
    USE SIGNAL ;
    ANTENNAGATEAREA 0.990000 ;
    PORT
      LAYER met3 ;
        RECT 0.000 270.680 4.000 271.280 ;
    END
  END a1[1]
  PIN a1[2]
    DIRECTION INPUT ;
    USE SIGNAL ;
    ANTENNAGATEAREA 0.852000 ;
    PORT
      LAYER met3 ;
        RECT 0.000 221.720 4.000 222.320 ;
    END
  END a1[2]
  PIN a1[3]
    DIRECTION INPUT ;
    USE SIGNAL ;
    ANTENNAGATEAREA 0.990000 ;
    PORT
      LAYER met3 ;
        RECT 0.000 172.760 4.000 173.360 ;
    END
  END a1[3]
  PIN a1[4]
    DIRECTION INPUT ;
    USE SIGNAL ;
    ANTENNAGATEAREA 0.990000 ;
    PORT
      LAYER met3 ;
        RECT 0.000 123.800 4.000 124.400 ;
    END
  END a1[4]
  PIN a2[0]
    DIRECTION INPUT ;
    USE SIGNAL ;
    ANTENNAGATEAREA 0.742500 ;
    ANTENNADIFFAREA 0.434700 ;
    PORT
      LAYER met3 ;
        RECT 0.000 564.440 4.000 565.040 ;
    END
  END a2[0]
  PIN a2[1]
    DIRECTION INPUT ;
    USE SIGNAL ;
    ANTENNAGATEAREA 0.990000 ;
    PORT
      LAYER met3 ;
        RECT 0.000 515.480 4.000 516.080 ;
    END
  END a2[1]
  PIN a2[2]
    DIRECTION INPUT ;
    USE SIGNAL ;
    ANTENNAGATEAREA 0.742500 ;
    PORT
      LAYER met3 ;
        RECT 0.000 466.520 4.000 467.120 ;
    END
  END a2[2]
  PIN a2[3]
    DIRECTION INPUT ;
    USE SIGNAL ;
    ANTENNAGATEAREA 0.247500 ;
    PORT
      LAYER met3 ;
        RECT 0.000 417.560 4.000 418.160 ;
    END
  END a2[3]
  PIN a2[4]
    DIRECTION INPUT ;
    USE SIGNAL ;
    ANTENNAGATEAREA 0.990000 ;
    PORT
      LAYER met3 ;
        RECT 0.000 368.600 4.000 369.200 ;
    END
  END a2[4]
  PIN a3[0]
    DIRECTION INPUT ;
    USE SIGNAL ;
    ANTENNAGATEAREA 0.852000 ;
    PORT
      LAYER met3 ;
        RECT 0.000 809.240 4.000 809.840 ;
    END
  END a3[0]
  PIN a3[1]
    DIRECTION INPUT ;
    USE SIGNAL ;
    ANTENNAGATEAREA 0.852000 ;
    PORT
      LAYER met3 ;
        RECT 0.000 760.280 4.000 760.880 ;
    END
  END a3[1]
  PIN a3[2]
    DIRECTION INPUT ;
    USE SIGNAL ;
    ANTENNAGATEAREA 0.990000 ;
    PORT
      LAYER met3 ;
        RECT 0.000 711.320 4.000 711.920 ;
    END
  END a3[2]
  PIN a3[3]
    DIRECTION INPUT ;
    USE SIGNAL ;
    ANTENNAGATEAREA 0.990000 ;
    PORT
      LAYER met3 ;
        RECT 0.000 662.360 4.000 662.960 ;
    END
  END a3[3]
  PIN a3[4]
    DIRECTION INPUT ;
    USE SIGNAL ;
    ANTENNAGATEAREA 0.990000 ;
    PORT
      LAYER met3 ;
        RECT 0.000 613.400 4.000 614.000 ;
    END
  END a3[4]
  PIN clk
    DIRECTION INPUT ;
    USE SIGNAL ;
    ANTENNAGATEAREA 0.852000 ;
    ANTENNADIFFAREA 0.869400 ;
    PORT
      LAYER met3 ;
        RECT 0.000 25.880 4.000 26.480 ;
    END
  END clk
  PIN rd1[0]
    DIRECTION OUTPUT ;
    USE SIGNAL ;
    ANTENNADIFFAREA 0.340600 ;
    PORT
      LAYER met3 ;
        RECT 2389.225 2361.000 2393.225 2361.600 ;
    END
  END rd1[0]
  PIN rd1[10]
    DIRECTION OUTPUT ;
    USE SIGNAL ;
    ANTENNADIFFAREA 0.340600 ;
    PORT
      LAYER met3 ;
        RECT 2389.225 1613.000 2393.225 1613.600 ;
    END
  END rd1[10]
  PIN rd1[11]
    DIRECTION OUTPUT ;
    USE SIGNAL ;
    ANTENNADIFFAREA 0.340600 ;
    PORT
      LAYER met3 ;
        RECT 2389.225 1538.200 2393.225 1538.800 ;
    END
  END rd1[11]
  PIN rd1[12]
    DIRECTION OUTPUT ;
    USE SIGNAL ;
    ANTENNADIFFAREA 0.340600 ;
    PORT
      LAYER met3 ;
        RECT 2389.225 1463.400 2393.225 1464.000 ;
    END
  END rd1[12]
  PIN rd1[13]
    DIRECTION OUTPUT ;
    USE SIGNAL ;
    ANTENNADIFFAREA 0.340600 ;
    PORT
      LAYER met3 ;
        RECT 2389.225 1388.600 2393.225 1389.200 ;
    END
  END rd1[13]
  PIN rd1[14]
    DIRECTION OUTPUT ;
    USE SIGNAL ;
    ANTENNADIFFAREA 0.340600 ;
    PORT
      LAYER met3 ;
        RECT 2389.225 1313.800 2393.225 1314.400 ;
    END
  END rd1[14]
  PIN rd1[15]
    DIRECTION OUTPUT ;
    USE SIGNAL ;
    ANTENNADIFFAREA 0.340600 ;
    PORT
      LAYER met3 ;
        RECT 2389.225 1239.000 2393.225 1239.600 ;
    END
  END rd1[15]
  PIN rd1[16]
    DIRECTION OUTPUT ;
    USE SIGNAL ;
    ANTENNADIFFAREA 0.340600 ;
    PORT
      LAYER met3 ;
        RECT 2389.225 1164.200 2393.225 1164.800 ;
    END
  END rd1[16]
  PIN rd1[17]
    DIRECTION OUTPUT ;
    USE SIGNAL ;
    ANTENNADIFFAREA 0.340600 ;
    PORT
      LAYER met3 ;
        RECT 2389.225 1089.400 2393.225 1090.000 ;
    END
  END rd1[17]
  PIN rd1[18]
    DIRECTION OUTPUT ;
    USE SIGNAL ;
    ANTENNADIFFAREA 0.340600 ;
    PORT
      LAYER met3 ;
        RECT 2389.225 1014.600 2393.225 1015.200 ;
    END
  END rd1[18]
  PIN rd1[19]
    DIRECTION OUTPUT ;
    USE SIGNAL ;
    ANTENNADIFFAREA 0.340600 ;
    PORT
      LAYER met3 ;
        RECT 2389.225 939.800 2393.225 940.400 ;
    END
  END rd1[19]
  PIN rd1[1]
    DIRECTION OUTPUT ;
    USE SIGNAL ;
    ANTENNADIFFAREA 0.340600 ;
    PORT
      LAYER met3 ;
        RECT 2389.225 2286.200 2393.225 2286.800 ;
    END
  END rd1[1]
  PIN rd1[20]
    DIRECTION OUTPUT ;
    USE SIGNAL ;
    ANTENNADIFFAREA 0.340600 ;
    PORT
      LAYER met3 ;
        RECT 2389.225 865.000 2393.225 865.600 ;
    END
  END rd1[20]
  PIN rd1[21]
    DIRECTION OUTPUT ;
    USE SIGNAL ;
    ANTENNADIFFAREA 0.340600 ;
    PORT
      LAYER met3 ;
        RECT 2389.225 790.200 2393.225 790.800 ;
    END
  END rd1[21]
  PIN rd1[22]
    DIRECTION OUTPUT ;
    USE SIGNAL ;
    ANTENNADIFFAREA 0.340600 ;
    PORT
      LAYER met3 ;
        RECT 2389.225 715.400 2393.225 716.000 ;
    END
  END rd1[22]
  PIN rd1[23]
    DIRECTION OUTPUT ;
    USE SIGNAL ;
    ANTENNADIFFAREA 0.340600 ;
    PORT
      LAYER met3 ;
        RECT 2389.225 640.600 2393.225 641.200 ;
    END
  END rd1[23]
  PIN rd1[24]
    DIRECTION OUTPUT ;
    USE SIGNAL ;
    ANTENNADIFFAREA 0.340600 ;
    PORT
      LAYER met3 ;
        RECT 2389.225 565.800 2393.225 566.400 ;
    END
  END rd1[24]
  PIN rd1[25]
    DIRECTION OUTPUT ;
    USE SIGNAL ;
    ANTENNADIFFAREA 0.340600 ;
    PORT
      LAYER met3 ;
        RECT 2389.225 491.000 2393.225 491.600 ;
    END
  END rd1[25]
  PIN rd1[26]
    DIRECTION OUTPUT ;
    USE SIGNAL ;
    ANTENNADIFFAREA 0.340600 ;
    PORT
      LAYER met3 ;
        RECT 2389.225 416.200 2393.225 416.800 ;
    END
  END rd1[26]
  PIN rd1[27]
    DIRECTION OUTPUT ;
    USE SIGNAL ;
    ANTENNADIFFAREA 0.340600 ;
    PORT
      LAYER met3 ;
        RECT 2389.225 341.400 2393.225 342.000 ;
    END
  END rd1[27]
  PIN rd1[28]
    DIRECTION OUTPUT ;
    USE SIGNAL ;
    ANTENNADIFFAREA 0.340600 ;
    PORT
      LAYER met3 ;
        RECT 2389.225 266.600 2393.225 267.200 ;
    END
  END rd1[28]
  PIN rd1[29]
    DIRECTION OUTPUT ;
    USE SIGNAL ;
    ANTENNADIFFAREA 0.340600 ;
    PORT
      LAYER met3 ;
        RECT 2389.225 191.800 2393.225 192.400 ;
    END
  END rd1[29]
  PIN rd1[2]
    DIRECTION OUTPUT ;
    USE SIGNAL ;
    ANTENNADIFFAREA 0.340600 ;
    PORT
      LAYER met3 ;
        RECT 2389.225 2211.400 2393.225 2212.000 ;
    END
  END rd1[2]
  PIN rd1[30]
    DIRECTION OUTPUT ;
    USE SIGNAL ;
    ANTENNADIFFAREA 0.340600 ;
    PORT
      LAYER met3 ;
        RECT 2389.225 117.000 2393.225 117.600 ;
    END
  END rd1[30]
  PIN rd1[31]
    DIRECTION OUTPUT ;
    USE SIGNAL ;
    ANTENNADIFFAREA 0.340600 ;
    PORT
      LAYER met3 ;
        RECT 2389.225 42.200 2393.225 42.800 ;
    END
  END rd1[31]
  PIN rd1[3]
    DIRECTION OUTPUT ;
    USE SIGNAL ;
    ANTENNADIFFAREA 0.340600 ;
    PORT
      LAYER met3 ;
        RECT 2389.225 2136.600 2393.225 2137.200 ;
    END
  END rd1[3]
  PIN rd1[4]
    DIRECTION OUTPUT ;
    USE SIGNAL ;
    ANTENNADIFFAREA 0.340600 ;
    PORT
      LAYER met3 ;
        RECT 2389.225 2061.800 2393.225 2062.400 ;
    END
  END rd1[4]
  PIN rd1[5]
    DIRECTION OUTPUT ;
    USE SIGNAL ;
    ANTENNADIFFAREA 0.340600 ;
    PORT
      LAYER met3 ;
        RECT 2389.225 1987.000 2393.225 1987.600 ;
    END
  END rd1[5]
  PIN rd1[6]
    DIRECTION OUTPUT ;
    USE SIGNAL ;
    ANTENNADIFFAREA 0.340600 ;
    PORT
      LAYER met3 ;
        RECT 2389.225 1912.200 2393.225 1912.800 ;
    END
  END rd1[6]
  PIN rd1[7]
    DIRECTION OUTPUT ;
    USE SIGNAL ;
    ANTENNADIFFAREA 0.340600 ;
    PORT
      LAYER met3 ;
        RECT 2389.225 1837.400 2393.225 1838.000 ;
    END
  END rd1[7]
  PIN rd1[8]
    DIRECTION OUTPUT ;
    USE SIGNAL ;
    ANTENNADIFFAREA 0.340600 ;
    PORT
      LAYER met3 ;
        RECT 2389.225 1762.600 2393.225 1763.200 ;
    END
  END rd1[8]
  PIN rd1[9]
    DIRECTION OUTPUT ;
    USE SIGNAL ;
    ANTENNADIFFAREA 0.340600 ;
    PORT
      LAYER met3 ;
        RECT 2389.225 1687.800 2393.225 1688.400 ;
    END
  END rd1[9]
  PIN rd2[0]
    DIRECTION OUTPUT ;
    USE SIGNAL ;
    ANTENNADIFFAREA 0.340600 ;
    PORT
      LAYER met2 ;
        RECT 2351.610 0.000 2351.890 4.000 ;
    END
  END rd2[0]
  PIN rd2[10]
    DIRECTION OUTPUT ;
    USE SIGNAL ;
    ANTENNADIFFAREA 0.340600 ;
    PORT
      LAYER met2 ;
        RECT 1606.410 0.000 1606.690 4.000 ;
    END
  END rd2[10]
  PIN rd2[11]
    DIRECTION OUTPUT ;
    USE SIGNAL ;
    ANTENNADIFFAREA 0.340600 ;
    PORT
      LAYER met2 ;
        RECT 1531.890 0.000 1532.170 4.000 ;
    END
  END rd2[11]
  PIN rd2[12]
    DIRECTION OUTPUT ;
    USE SIGNAL ;
    ANTENNADIFFAREA 0.340600 ;
    PORT
      LAYER met2 ;
        RECT 1457.370 0.000 1457.650 4.000 ;
    END
  END rd2[12]
  PIN rd2[13]
    DIRECTION OUTPUT ;
    USE SIGNAL ;
    ANTENNADIFFAREA 0.340600 ;
    PORT
      LAYER met2 ;
        RECT 1382.850 0.000 1383.130 4.000 ;
    END
  END rd2[13]
  PIN rd2[14]
    DIRECTION OUTPUT ;
    USE SIGNAL ;
    ANTENNADIFFAREA 0.340600 ;
    PORT
      LAYER met2 ;
        RECT 1308.330 0.000 1308.610 4.000 ;
    END
  END rd2[14]
  PIN rd2[15]
    DIRECTION OUTPUT ;
    USE SIGNAL ;
    ANTENNADIFFAREA 0.340600 ;
    PORT
      LAYER met2 ;
        RECT 1233.810 0.000 1234.090 4.000 ;
    END
  END rd2[15]
  PIN rd2[16]
    DIRECTION OUTPUT ;
    USE SIGNAL ;
    ANTENNADIFFAREA 0.340600 ;
    PORT
      LAYER met2 ;
        RECT 1159.290 0.000 1159.570 4.000 ;
    END
  END rd2[16]
  PIN rd2[17]
    DIRECTION OUTPUT ;
    USE SIGNAL ;
    ANTENNADIFFAREA 0.340600 ;
    PORT
      LAYER met2 ;
        RECT 1084.770 0.000 1085.050 4.000 ;
    END
  END rd2[17]
  PIN rd2[18]
    DIRECTION OUTPUT ;
    USE SIGNAL ;
    ANTENNADIFFAREA 0.340600 ;
    PORT
      LAYER met2 ;
        RECT 1010.250 0.000 1010.530 4.000 ;
    END
  END rd2[18]
  PIN rd2[19]
    DIRECTION OUTPUT ;
    USE SIGNAL ;
    ANTENNADIFFAREA 0.340600 ;
    PORT
      LAYER met2 ;
        RECT 935.730 0.000 936.010 4.000 ;
    END
  END rd2[19]
  PIN rd2[1]
    DIRECTION OUTPUT ;
    USE SIGNAL ;
    ANTENNADIFFAREA 0.340600 ;
    PORT
      LAYER met2 ;
        RECT 2277.090 0.000 2277.370 4.000 ;
    END
  END rd2[1]
  PIN rd2[20]
    DIRECTION OUTPUT ;
    USE SIGNAL ;
    ANTENNADIFFAREA 0.340600 ;
    PORT
      LAYER met2 ;
        RECT 861.210 0.000 861.490 4.000 ;
    END
  END rd2[20]
  PIN rd2[21]
    DIRECTION OUTPUT ;
    USE SIGNAL ;
    ANTENNADIFFAREA 0.340600 ;
    PORT
      LAYER met2 ;
        RECT 786.690 0.000 786.970 4.000 ;
    END
  END rd2[21]
  PIN rd2[22]
    DIRECTION OUTPUT ;
    USE SIGNAL ;
    ANTENNADIFFAREA 0.340600 ;
    PORT
      LAYER met2 ;
        RECT 712.170 0.000 712.450 4.000 ;
    END
  END rd2[22]
  PIN rd2[23]
    DIRECTION OUTPUT ;
    USE SIGNAL ;
    ANTENNADIFFAREA 0.340600 ;
    PORT
      LAYER met2 ;
        RECT 637.650 0.000 637.930 4.000 ;
    END
  END rd2[23]
  PIN rd2[24]
    DIRECTION OUTPUT ;
    USE SIGNAL ;
    ANTENNADIFFAREA 0.340600 ;
    PORT
      LAYER met2 ;
        RECT 563.130 0.000 563.410 4.000 ;
    END
  END rd2[24]
  PIN rd2[25]
    DIRECTION OUTPUT ;
    USE SIGNAL ;
    ANTENNADIFFAREA 0.340600 ;
    PORT
      LAYER met2 ;
        RECT 488.610 0.000 488.890 4.000 ;
    END
  END rd2[25]
  PIN rd2[26]
    DIRECTION OUTPUT ;
    USE SIGNAL ;
    ANTENNADIFFAREA 0.340600 ;
    PORT
      LAYER met2 ;
        RECT 414.090 0.000 414.370 4.000 ;
    END
  END rd2[26]
  PIN rd2[27]
    DIRECTION OUTPUT ;
    USE SIGNAL ;
    ANTENNADIFFAREA 0.340600 ;
    PORT
      LAYER met2 ;
        RECT 339.570 0.000 339.850 4.000 ;
    END
  END rd2[27]
  PIN rd2[28]
    DIRECTION OUTPUT ;
    USE SIGNAL ;
    ANTENNADIFFAREA 0.340600 ;
    PORT
      LAYER met2 ;
        RECT 265.050 0.000 265.330 4.000 ;
    END
  END rd2[28]
  PIN rd2[29]
    DIRECTION OUTPUT ;
    USE SIGNAL ;
    ANTENNADIFFAREA 0.340600 ;
    PORT
      LAYER met2 ;
        RECT 190.530 0.000 190.810 4.000 ;
    END
  END rd2[29]
  PIN rd2[2]
    DIRECTION OUTPUT ;
    USE SIGNAL ;
    ANTENNADIFFAREA 0.340600 ;
    PORT
      LAYER met2 ;
        RECT 2202.570 0.000 2202.850 4.000 ;
    END
  END rd2[2]
  PIN rd2[30]
    DIRECTION OUTPUT ;
    USE SIGNAL ;
    ANTENNADIFFAREA 0.340600 ;
    PORT
      LAYER met2 ;
        RECT 116.010 0.000 116.290 4.000 ;
    END
  END rd2[30]
  PIN rd2[31]
    DIRECTION OUTPUT ;
    USE SIGNAL ;
    ANTENNADIFFAREA 0.340600 ;
    PORT
      LAYER met2 ;
        RECT 41.490 0.000 41.770 4.000 ;
    END
  END rd2[31]
  PIN rd2[3]
    DIRECTION OUTPUT ;
    USE SIGNAL ;
    ANTENNADIFFAREA 0.340600 ;
    PORT
      LAYER met2 ;
        RECT 2128.050 0.000 2128.330 4.000 ;
    END
  END rd2[3]
  PIN rd2[4]
    DIRECTION OUTPUT ;
    USE SIGNAL ;
    ANTENNADIFFAREA 0.340600 ;
    PORT
      LAYER met2 ;
        RECT 2053.530 0.000 2053.810 4.000 ;
    END
  END rd2[4]
  PIN rd2[5]
    DIRECTION OUTPUT ;
    USE SIGNAL ;
    ANTENNADIFFAREA 0.340600 ;
    PORT
      LAYER met2 ;
        RECT 1979.010 0.000 1979.290 4.000 ;
    END
  END rd2[5]
  PIN rd2[6]
    DIRECTION OUTPUT ;
    USE SIGNAL ;
    ANTENNADIFFAREA 0.340600 ;
    PORT
      LAYER met2 ;
        RECT 1904.490 0.000 1904.770 4.000 ;
    END
  END rd2[6]
  PIN rd2[7]
    DIRECTION OUTPUT ;
    USE SIGNAL ;
    ANTENNADIFFAREA 0.340600 ;
    PORT
      LAYER met2 ;
        RECT 1829.970 0.000 1830.250 4.000 ;
    END
  END rd2[7]
  PIN rd2[8]
    DIRECTION OUTPUT ;
    USE SIGNAL ;
    ANTENNADIFFAREA 0.340600 ;
    PORT
      LAYER met2 ;
        RECT 1755.450 0.000 1755.730 4.000 ;
    END
  END rd2[8]
  PIN rd2[9]
    DIRECTION OUTPUT ;
    USE SIGNAL ;
    ANTENNADIFFAREA 0.340600 ;
    PORT
      LAYER met2 ;
        RECT 1680.930 0.000 1681.210 4.000 ;
    END
  END rd2[9]
  PIN wd3[0]
    DIRECTION INPUT ;
    USE SIGNAL ;
    ANTENNAGATEAREA 0.990000 ;
    PORT
      LAYER met3 ;
        RECT 0.000 2375.960 4.000 2376.560 ;
    END
  END wd3[0]
  PIN wd3[10]
    DIRECTION INPUT ;
    USE SIGNAL ;
    ANTENNAGATEAREA 0.990000 ;
    PORT
      LAYER met3 ;
        RECT 0.000 1886.360 4.000 1886.960 ;
    END
  END wd3[10]
  PIN wd3[11]
    DIRECTION INPUT ;
    USE SIGNAL ;
    ANTENNAGATEAREA 0.990000 ;
    PORT
      LAYER met3 ;
        RECT 0.000 1837.400 4.000 1838.000 ;
    END
  END wd3[11]
  PIN wd3[12]
    DIRECTION INPUT ;
    USE SIGNAL ;
    ANTENNAGATEAREA 0.990000 ;
    PORT
      LAYER met3 ;
        RECT 0.000 1788.440 4.000 1789.040 ;
    END
  END wd3[12]
  PIN wd3[13]
    DIRECTION INPUT ;
    USE SIGNAL ;
    ANTENNAGATEAREA 0.852000 ;
    PORT
      LAYER met3 ;
        RECT 0.000 1739.480 4.000 1740.080 ;
    END
  END wd3[13]
  PIN wd3[14]
    DIRECTION INPUT ;
    USE SIGNAL ;
    ANTENNAGATEAREA 0.852000 ;
    PORT
      LAYER met3 ;
        RECT 0.000 1690.520 4.000 1691.120 ;
    END
  END wd3[14]
  PIN wd3[15]
    DIRECTION INPUT ;
    USE SIGNAL ;
    ANTENNAGATEAREA 0.990000 ;
    PORT
      LAYER met3 ;
        RECT 0.000 1641.560 4.000 1642.160 ;
    END
  END wd3[15]
  PIN wd3[16]
    DIRECTION INPUT ;
    USE SIGNAL ;
    ANTENNAGATEAREA 0.852000 ;
    PORT
      LAYER met3 ;
        RECT 0.000 1592.600 4.000 1593.200 ;
    END
  END wd3[16]
  PIN wd3[17]
    DIRECTION INPUT ;
    USE SIGNAL ;
    ANTENNAGATEAREA 0.990000 ;
    PORT
      LAYER met3 ;
        RECT 0.000 1543.640 4.000 1544.240 ;
    END
  END wd3[17]
  PIN wd3[18]
    DIRECTION INPUT ;
    USE SIGNAL ;
    ANTENNAGATEAREA 0.990000 ;
    PORT
      LAYER met3 ;
        RECT 0.000 1494.680 4.000 1495.280 ;
    END
  END wd3[18]
  PIN wd3[19]
    DIRECTION INPUT ;
    USE SIGNAL ;
    ANTENNAGATEAREA 0.990000 ;
    PORT
      LAYER met3 ;
        RECT 0.000 1445.720 4.000 1446.320 ;
    END
  END wd3[19]
  PIN wd3[1]
    DIRECTION INPUT ;
    USE SIGNAL ;
    ANTENNAGATEAREA 0.990000 ;
    PORT
      LAYER met3 ;
        RECT 0.000 2327.000 4.000 2327.600 ;
    END
  END wd3[1]
  PIN wd3[20]
    DIRECTION INPUT ;
    USE SIGNAL ;
    ANTENNAGATEAREA 0.990000 ;
    PORT
      LAYER met3 ;
        RECT 0.000 1396.760 4.000 1397.360 ;
    END
  END wd3[20]
  PIN wd3[21]
    DIRECTION INPUT ;
    USE SIGNAL ;
    ANTENNAGATEAREA 0.990000 ;
    PORT
      LAYER met3 ;
        RECT 0.000 1347.800 4.000 1348.400 ;
    END
  END wd3[21]
  PIN wd3[22]
    DIRECTION INPUT ;
    USE SIGNAL ;
    ANTENNAGATEAREA 0.990000 ;
    PORT
      LAYER met3 ;
        RECT 0.000 1298.840 4.000 1299.440 ;
    END
  END wd3[22]
  PIN wd3[23]
    DIRECTION INPUT ;
    USE SIGNAL ;
    ANTENNAGATEAREA 0.990000 ;
    PORT
      LAYER met3 ;
        RECT 0.000 1249.880 4.000 1250.480 ;
    END
  END wd3[23]
  PIN wd3[24]
    DIRECTION INPUT ;
    USE SIGNAL ;
    ANTENNAGATEAREA 0.990000 ;
    PORT
      LAYER met3 ;
        RECT 0.000 1200.920 4.000 1201.520 ;
    END
  END wd3[24]
  PIN wd3[25]
    DIRECTION INPUT ;
    USE SIGNAL ;
    ANTENNAGATEAREA 0.852000 ;
    PORT
      LAYER met3 ;
        RECT 0.000 1151.960 4.000 1152.560 ;
    END
  END wd3[25]
  PIN wd3[26]
    DIRECTION INPUT ;
    USE SIGNAL ;
    ANTENNAGATEAREA 0.852000 ;
    PORT
      LAYER met3 ;
        RECT 0.000 1103.000 4.000 1103.600 ;
    END
  END wd3[26]
  PIN wd3[27]
    DIRECTION INPUT ;
    USE SIGNAL ;
    ANTENNAGATEAREA 0.990000 ;
    PORT
      LAYER met3 ;
        RECT 0.000 1054.040 4.000 1054.640 ;
    END
  END wd3[27]
  PIN wd3[28]
    DIRECTION INPUT ;
    USE SIGNAL ;
    ANTENNAGATEAREA 0.852000 ;
    PORT
      LAYER met3 ;
        RECT 0.000 1005.080 4.000 1005.680 ;
    END
  END wd3[28]
  PIN wd3[29]
    DIRECTION INPUT ;
    USE SIGNAL ;
    ANTENNAGATEAREA 0.852000 ;
    PORT
      LAYER met3 ;
        RECT 0.000 956.120 4.000 956.720 ;
    END
  END wd3[29]
  PIN wd3[2]
    DIRECTION INPUT ;
    USE SIGNAL ;
    ANTENNAGATEAREA 0.990000 ;
    PORT
      LAYER met3 ;
        RECT 0.000 2278.040 4.000 2278.640 ;
    END
  END wd3[2]
  PIN wd3[30]
    DIRECTION INPUT ;
    USE SIGNAL ;
    ANTENNAGATEAREA 0.990000 ;
    PORT
      LAYER met3 ;
        RECT 0.000 907.160 4.000 907.760 ;
    END
  END wd3[30]
  PIN wd3[31]
    DIRECTION INPUT ;
    USE SIGNAL ;
    ANTENNAGATEAREA 0.990000 ;
    PORT
      LAYER met3 ;
        RECT 0.000 858.200 4.000 858.800 ;
    END
  END wd3[31]
  PIN wd3[3]
    DIRECTION INPUT ;
    USE SIGNAL ;
    ANTENNAGATEAREA 0.990000 ;
    PORT
      LAYER met3 ;
        RECT 0.000 2229.080 4.000 2229.680 ;
    END
  END wd3[3]
  PIN wd3[4]
    DIRECTION INPUT ;
    USE SIGNAL ;
    ANTENNAGATEAREA 0.852000 ;
    PORT
      LAYER met3 ;
        RECT 0.000 2180.120 4.000 2180.720 ;
    END
  END wd3[4]
  PIN wd3[5]
    DIRECTION INPUT ;
    USE SIGNAL ;
    ANTENNAGATEAREA 0.852000 ;
    PORT
      LAYER met3 ;
        RECT 0.000 2131.160 4.000 2131.760 ;
    END
  END wd3[5]
  PIN wd3[6]
    DIRECTION INPUT ;
    USE SIGNAL ;
    ANTENNAGATEAREA 0.852000 ;
    PORT
      LAYER met3 ;
        RECT 0.000 2082.200 4.000 2082.800 ;
    END
  END wd3[6]
  PIN wd3[7]
    DIRECTION INPUT ;
    USE SIGNAL ;
    ANTENNAGATEAREA 0.990000 ;
    PORT
      LAYER met3 ;
        RECT 0.000 2033.240 4.000 2033.840 ;
    END
  END wd3[7]
  PIN wd3[8]
    DIRECTION INPUT ;
    USE SIGNAL ;
    ANTENNAGATEAREA 0.852000 ;
    PORT
      LAYER met3 ;
        RECT 0.000 1984.280 4.000 1984.880 ;
    END
  END wd3[8]
  PIN wd3[9]
    DIRECTION INPUT ;
    USE SIGNAL ;
    ANTENNAGATEAREA 0.990000 ;
    PORT
      LAYER met3 ;
        RECT 0.000 1935.320 4.000 1935.920 ;
    END
  END wd3[9]
  PIN we3
    DIRECTION INPUT ;
    USE SIGNAL ;
    ANTENNAGATEAREA 0.852000 ;
    PORT
      LAYER met3 ;
        RECT 0.000 74.840 4.000 75.440 ;
    END
  END we3
  OBS
      LAYER nwell ;
        RECT 5.330 10.795 2387.590 2391.070 ;
      LAYER li1 ;
        RECT 5.520 10.795 2387.400 2390.965 ;
      LAYER met1 ;
        RECT 4.210 8.880 2387.700 2393.220 ;
      LAYER met2 ;
        RECT 4.230 4.280 2387.310 2393.250 ;
        RECT 4.230 4.000 41.210 4.280 ;
        RECT 42.050 4.000 115.730 4.280 ;
        RECT 116.570 4.000 190.250 4.280 ;
        RECT 191.090 4.000 264.770 4.280 ;
        RECT 265.610 4.000 339.290 4.280 ;
        RECT 340.130 4.000 413.810 4.280 ;
        RECT 414.650 4.000 488.330 4.280 ;
        RECT 489.170 4.000 562.850 4.280 ;
        RECT 563.690 4.000 637.370 4.280 ;
        RECT 638.210 4.000 711.890 4.280 ;
        RECT 712.730 4.000 786.410 4.280 ;
        RECT 787.250 4.000 860.930 4.280 ;
        RECT 861.770 4.000 935.450 4.280 ;
        RECT 936.290 4.000 1009.970 4.280 ;
        RECT 1010.810 4.000 1084.490 4.280 ;
        RECT 1085.330 4.000 1159.010 4.280 ;
        RECT 1159.850 4.000 1233.530 4.280 ;
        RECT 1234.370 4.000 1308.050 4.280 ;
        RECT 1308.890 4.000 1382.570 4.280 ;
        RECT 1383.410 4.000 1457.090 4.280 ;
        RECT 1457.930 4.000 1531.610 4.280 ;
        RECT 1532.450 4.000 1606.130 4.280 ;
        RECT 1606.970 4.000 1680.650 4.280 ;
        RECT 1681.490 4.000 1755.170 4.280 ;
        RECT 1756.010 4.000 1829.690 4.280 ;
        RECT 1830.530 4.000 1904.210 4.280 ;
        RECT 1905.050 4.000 1978.730 4.280 ;
        RECT 1979.570 4.000 2053.250 4.280 ;
        RECT 2054.090 4.000 2127.770 4.280 ;
        RECT 2128.610 4.000 2202.290 4.280 ;
        RECT 2203.130 4.000 2276.810 4.280 ;
        RECT 2277.650 4.000 2351.330 4.280 ;
        RECT 2352.170 4.000 2387.310 4.280 ;
      LAYER met3 ;
        RECT 3.990 2376.960 2389.225 2391.045 ;
        RECT 4.400 2375.560 2389.225 2376.960 ;
        RECT 3.990 2362.000 2389.225 2375.560 ;
        RECT 3.990 2360.600 2388.825 2362.000 ;
        RECT 3.990 2328.000 2389.225 2360.600 ;
        RECT 4.400 2326.600 2389.225 2328.000 ;
        RECT 3.990 2287.200 2389.225 2326.600 ;
        RECT 3.990 2285.800 2388.825 2287.200 ;
        RECT 3.990 2279.040 2389.225 2285.800 ;
        RECT 4.400 2277.640 2389.225 2279.040 ;
        RECT 3.990 2230.080 2389.225 2277.640 ;
        RECT 4.400 2228.680 2389.225 2230.080 ;
        RECT 3.990 2212.400 2389.225 2228.680 ;
        RECT 3.990 2211.000 2388.825 2212.400 ;
        RECT 3.990 2181.120 2389.225 2211.000 ;
        RECT 4.400 2179.720 2389.225 2181.120 ;
        RECT 3.990 2137.600 2389.225 2179.720 ;
        RECT 3.990 2136.200 2388.825 2137.600 ;
        RECT 3.990 2132.160 2389.225 2136.200 ;
        RECT 4.400 2130.760 2389.225 2132.160 ;
        RECT 3.990 2083.200 2389.225 2130.760 ;
        RECT 4.400 2081.800 2389.225 2083.200 ;
        RECT 3.990 2062.800 2389.225 2081.800 ;
        RECT 3.990 2061.400 2388.825 2062.800 ;
        RECT 3.990 2034.240 2389.225 2061.400 ;
        RECT 4.400 2032.840 2389.225 2034.240 ;
        RECT 3.990 1988.000 2389.225 2032.840 ;
        RECT 3.990 1986.600 2388.825 1988.000 ;
        RECT 3.990 1985.280 2389.225 1986.600 ;
        RECT 4.400 1983.880 2389.225 1985.280 ;
        RECT 3.990 1936.320 2389.225 1983.880 ;
        RECT 4.400 1934.920 2389.225 1936.320 ;
        RECT 3.990 1913.200 2389.225 1934.920 ;
        RECT 3.990 1911.800 2388.825 1913.200 ;
        RECT 3.990 1887.360 2389.225 1911.800 ;
        RECT 4.400 1885.960 2389.225 1887.360 ;
        RECT 3.990 1838.400 2389.225 1885.960 ;
        RECT 4.400 1837.000 2388.825 1838.400 ;
        RECT 3.990 1789.440 2389.225 1837.000 ;
        RECT 4.400 1788.040 2389.225 1789.440 ;
        RECT 3.990 1763.600 2389.225 1788.040 ;
        RECT 3.990 1762.200 2388.825 1763.600 ;
        RECT 3.990 1740.480 2389.225 1762.200 ;
        RECT 4.400 1739.080 2389.225 1740.480 ;
        RECT 3.990 1691.520 2389.225 1739.080 ;
        RECT 4.400 1690.120 2389.225 1691.520 ;
        RECT 3.990 1688.800 2389.225 1690.120 ;
        RECT 3.990 1687.400 2388.825 1688.800 ;
        RECT 3.990 1642.560 2389.225 1687.400 ;
        RECT 4.400 1641.160 2389.225 1642.560 ;
        RECT 3.990 1614.000 2389.225 1641.160 ;
        RECT 3.990 1612.600 2388.825 1614.000 ;
        RECT 3.990 1593.600 2389.225 1612.600 ;
        RECT 4.400 1592.200 2389.225 1593.600 ;
        RECT 3.990 1544.640 2389.225 1592.200 ;
        RECT 4.400 1543.240 2389.225 1544.640 ;
        RECT 3.990 1539.200 2389.225 1543.240 ;
        RECT 3.990 1537.800 2388.825 1539.200 ;
        RECT 3.990 1495.680 2389.225 1537.800 ;
        RECT 4.400 1494.280 2389.225 1495.680 ;
        RECT 3.990 1464.400 2389.225 1494.280 ;
        RECT 3.990 1463.000 2388.825 1464.400 ;
        RECT 3.990 1446.720 2389.225 1463.000 ;
        RECT 4.400 1445.320 2389.225 1446.720 ;
        RECT 3.990 1397.760 2389.225 1445.320 ;
        RECT 4.400 1396.360 2389.225 1397.760 ;
        RECT 3.990 1389.600 2389.225 1396.360 ;
        RECT 3.990 1388.200 2388.825 1389.600 ;
        RECT 3.990 1348.800 2389.225 1388.200 ;
        RECT 4.400 1347.400 2389.225 1348.800 ;
        RECT 3.990 1314.800 2389.225 1347.400 ;
        RECT 3.990 1313.400 2388.825 1314.800 ;
        RECT 3.990 1299.840 2389.225 1313.400 ;
        RECT 4.400 1298.440 2389.225 1299.840 ;
        RECT 3.990 1250.880 2389.225 1298.440 ;
        RECT 4.400 1249.480 2389.225 1250.880 ;
        RECT 3.990 1240.000 2389.225 1249.480 ;
        RECT 3.990 1238.600 2388.825 1240.000 ;
        RECT 3.990 1201.920 2389.225 1238.600 ;
        RECT 4.400 1200.520 2389.225 1201.920 ;
        RECT 3.990 1165.200 2389.225 1200.520 ;
        RECT 3.990 1163.800 2388.825 1165.200 ;
        RECT 3.990 1152.960 2389.225 1163.800 ;
        RECT 4.400 1151.560 2389.225 1152.960 ;
        RECT 3.990 1104.000 2389.225 1151.560 ;
        RECT 4.400 1102.600 2389.225 1104.000 ;
        RECT 3.990 1090.400 2389.225 1102.600 ;
        RECT 3.990 1089.000 2388.825 1090.400 ;
        RECT 3.990 1055.040 2389.225 1089.000 ;
        RECT 4.400 1053.640 2389.225 1055.040 ;
        RECT 3.990 1015.600 2389.225 1053.640 ;
        RECT 3.990 1014.200 2388.825 1015.600 ;
        RECT 3.990 1006.080 2389.225 1014.200 ;
        RECT 4.400 1004.680 2389.225 1006.080 ;
        RECT 3.990 957.120 2389.225 1004.680 ;
        RECT 4.400 955.720 2389.225 957.120 ;
        RECT 3.990 940.800 2389.225 955.720 ;
        RECT 3.990 939.400 2388.825 940.800 ;
        RECT 3.990 908.160 2389.225 939.400 ;
        RECT 4.400 906.760 2389.225 908.160 ;
        RECT 3.990 866.000 2389.225 906.760 ;
        RECT 3.990 864.600 2388.825 866.000 ;
        RECT 3.990 859.200 2389.225 864.600 ;
        RECT 4.400 857.800 2389.225 859.200 ;
        RECT 3.990 810.240 2389.225 857.800 ;
        RECT 4.400 808.840 2389.225 810.240 ;
        RECT 3.990 791.200 2389.225 808.840 ;
        RECT 3.990 789.800 2388.825 791.200 ;
        RECT 3.990 761.280 2389.225 789.800 ;
        RECT 4.400 759.880 2389.225 761.280 ;
        RECT 3.990 716.400 2389.225 759.880 ;
        RECT 3.990 715.000 2388.825 716.400 ;
        RECT 3.990 712.320 2389.225 715.000 ;
        RECT 4.400 710.920 2389.225 712.320 ;
        RECT 3.990 663.360 2389.225 710.920 ;
        RECT 4.400 661.960 2389.225 663.360 ;
        RECT 3.990 641.600 2389.225 661.960 ;
        RECT 3.990 640.200 2388.825 641.600 ;
        RECT 3.990 614.400 2389.225 640.200 ;
        RECT 4.400 613.000 2389.225 614.400 ;
        RECT 3.990 566.800 2389.225 613.000 ;
        RECT 3.990 565.440 2388.825 566.800 ;
        RECT 4.400 565.400 2388.825 565.440 ;
        RECT 4.400 564.040 2389.225 565.400 ;
        RECT 3.990 516.480 2389.225 564.040 ;
        RECT 4.400 515.080 2389.225 516.480 ;
        RECT 3.990 492.000 2389.225 515.080 ;
        RECT 3.990 490.600 2388.825 492.000 ;
        RECT 3.990 467.520 2389.225 490.600 ;
        RECT 4.400 466.120 2389.225 467.520 ;
        RECT 3.990 418.560 2389.225 466.120 ;
        RECT 4.400 417.200 2389.225 418.560 ;
        RECT 4.400 417.160 2388.825 417.200 ;
        RECT 3.990 415.800 2388.825 417.160 ;
        RECT 3.990 369.600 2389.225 415.800 ;
        RECT 4.400 368.200 2389.225 369.600 ;
        RECT 3.990 342.400 2389.225 368.200 ;
        RECT 3.990 341.000 2388.825 342.400 ;
        RECT 3.990 320.640 2389.225 341.000 ;
        RECT 4.400 319.240 2389.225 320.640 ;
        RECT 3.990 271.680 2389.225 319.240 ;
        RECT 4.400 270.280 2389.225 271.680 ;
        RECT 3.990 267.600 2389.225 270.280 ;
        RECT 3.990 266.200 2388.825 267.600 ;
        RECT 3.990 222.720 2389.225 266.200 ;
        RECT 4.400 221.320 2389.225 222.720 ;
        RECT 3.990 192.800 2389.225 221.320 ;
        RECT 3.990 191.400 2388.825 192.800 ;
        RECT 3.990 173.760 2389.225 191.400 ;
        RECT 4.400 172.360 2389.225 173.760 ;
        RECT 3.990 124.800 2389.225 172.360 ;
        RECT 4.400 123.400 2389.225 124.800 ;
        RECT 3.990 118.000 2389.225 123.400 ;
        RECT 3.990 116.600 2388.825 118.000 ;
        RECT 3.990 75.840 2389.225 116.600 ;
        RECT 4.400 74.440 2389.225 75.840 ;
        RECT 3.990 43.200 2389.225 74.440 ;
        RECT 3.990 41.800 2388.825 43.200 ;
        RECT 3.990 26.880 2389.225 41.800 ;
        RECT 4.400 25.480 2389.225 26.880 ;
        RECT 3.990 10.715 2389.225 25.480 ;
      LAYER met4 ;
        RECT 26.975 19.895 34.320 2389.345 ;
        RECT 36.720 19.895 37.620 2389.345 ;
        RECT 40.020 19.895 59.320 2389.345 ;
        RECT 61.720 19.895 62.620 2389.345 ;
        RECT 65.020 19.895 84.320 2389.345 ;
        RECT 86.720 19.895 87.620 2389.345 ;
        RECT 90.020 19.895 109.320 2389.345 ;
        RECT 111.720 19.895 112.620 2389.345 ;
        RECT 115.020 19.895 134.320 2389.345 ;
        RECT 136.720 19.895 137.620 2389.345 ;
        RECT 140.020 19.895 159.320 2389.345 ;
        RECT 161.720 19.895 162.620 2389.345 ;
        RECT 165.020 19.895 184.320 2389.345 ;
        RECT 186.720 19.895 187.620 2389.345 ;
        RECT 190.020 19.895 209.320 2389.345 ;
        RECT 211.720 19.895 212.620 2389.345 ;
        RECT 215.020 19.895 234.320 2389.345 ;
        RECT 236.720 19.895 237.620 2389.345 ;
        RECT 240.020 19.895 259.320 2389.345 ;
        RECT 261.720 19.895 262.620 2389.345 ;
        RECT 265.020 19.895 284.320 2389.345 ;
        RECT 286.720 19.895 287.620 2389.345 ;
        RECT 290.020 19.895 309.320 2389.345 ;
        RECT 311.720 19.895 312.620 2389.345 ;
        RECT 315.020 19.895 334.320 2389.345 ;
        RECT 336.720 19.895 337.620 2389.345 ;
        RECT 340.020 19.895 359.320 2389.345 ;
        RECT 361.720 19.895 362.620 2389.345 ;
        RECT 365.020 19.895 384.320 2389.345 ;
        RECT 386.720 19.895 387.620 2389.345 ;
        RECT 390.020 19.895 409.320 2389.345 ;
        RECT 411.720 19.895 412.620 2389.345 ;
        RECT 415.020 19.895 434.320 2389.345 ;
        RECT 436.720 19.895 437.620 2389.345 ;
        RECT 440.020 19.895 459.320 2389.345 ;
        RECT 461.720 19.895 462.620 2389.345 ;
        RECT 465.020 19.895 484.320 2389.345 ;
        RECT 486.720 19.895 487.620 2389.345 ;
        RECT 490.020 19.895 509.320 2389.345 ;
        RECT 511.720 19.895 512.620 2389.345 ;
        RECT 515.020 19.895 534.320 2389.345 ;
        RECT 536.720 19.895 537.620 2389.345 ;
        RECT 540.020 19.895 559.320 2389.345 ;
        RECT 561.720 19.895 562.620 2389.345 ;
        RECT 565.020 19.895 584.320 2389.345 ;
        RECT 586.720 19.895 587.620 2389.345 ;
        RECT 590.020 19.895 609.320 2389.345 ;
        RECT 611.720 19.895 612.620 2389.345 ;
        RECT 615.020 19.895 634.320 2389.345 ;
        RECT 636.720 19.895 637.620 2389.345 ;
        RECT 640.020 19.895 659.320 2389.345 ;
        RECT 661.720 19.895 662.620 2389.345 ;
        RECT 665.020 19.895 684.320 2389.345 ;
        RECT 686.720 19.895 687.620 2389.345 ;
        RECT 690.020 19.895 709.320 2389.345 ;
        RECT 711.720 19.895 712.620 2389.345 ;
        RECT 715.020 19.895 734.320 2389.345 ;
        RECT 736.720 19.895 737.620 2389.345 ;
        RECT 740.020 19.895 759.320 2389.345 ;
        RECT 761.720 19.895 762.620 2389.345 ;
        RECT 765.020 19.895 784.320 2389.345 ;
        RECT 786.720 19.895 787.620 2389.345 ;
        RECT 790.020 19.895 809.320 2389.345 ;
        RECT 811.720 19.895 812.620 2389.345 ;
        RECT 815.020 19.895 834.320 2389.345 ;
        RECT 836.720 19.895 837.620 2389.345 ;
        RECT 840.020 19.895 859.320 2389.345 ;
        RECT 861.720 19.895 862.620 2389.345 ;
        RECT 865.020 19.895 884.320 2389.345 ;
        RECT 886.720 19.895 887.620 2389.345 ;
        RECT 890.020 19.895 909.320 2389.345 ;
        RECT 911.720 19.895 912.620 2389.345 ;
        RECT 915.020 19.895 934.320 2389.345 ;
        RECT 936.720 19.895 937.620 2389.345 ;
        RECT 940.020 19.895 959.320 2389.345 ;
        RECT 961.720 19.895 962.620 2389.345 ;
        RECT 965.020 19.895 984.320 2389.345 ;
        RECT 986.720 19.895 987.620 2389.345 ;
        RECT 990.020 19.895 1009.320 2389.345 ;
        RECT 1011.720 19.895 1012.620 2389.345 ;
        RECT 1015.020 19.895 1034.320 2389.345 ;
        RECT 1036.720 19.895 1037.620 2389.345 ;
        RECT 1040.020 19.895 1059.320 2389.345 ;
        RECT 1061.720 19.895 1062.620 2389.345 ;
        RECT 1065.020 19.895 1084.320 2389.345 ;
        RECT 1086.720 19.895 1087.620 2389.345 ;
        RECT 1090.020 19.895 1109.320 2389.345 ;
        RECT 1111.720 19.895 1112.620 2389.345 ;
        RECT 1115.020 19.895 1134.320 2389.345 ;
        RECT 1136.720 19.895 1137.620 2389.345 ;
        RECT 1140.020 19.895 1159.320 2389.345 ;
        RECT 1161.720 19.895 1162.620 2389.345 ;
        RECT 1165.020 19.895 1184.320 2389.345 ;
        RECT 1186.720 19.895 1187.620 2389.345 ;
        RECT 1190.020 19.895 1209.320 2389.345 ;
        RECT 1211.720 19.895 1212.620 2389.345 ;
        RECT 1215.020 19.895 1234.320 2389.345 ;
        RECT 1236.720 19.895 1237.620 2389.345 ;
        RECT 1240.020 19.895 1259.320 2389.345 ;
        RECT 1261.720 19.895 1262.620 2389.345 ;
        RECT 1265.020 19.895 1284.320 2389.345 ;
        RECT 1286.720 19.895 1287.620 2389.345 ;
        RECT 1290.020 19.895 1309.320 2389.345 ;
        RECT 1311.720 19.895 1312.620 2389.345 ;
        RECT 1315.020 19.895 1334.320 2389.345 ;
        RECT 1336.720 19.895 1337.620 2389.345 ;
        RECT 1340.020 19.895 1359.320 2389.345 ;
        RECT 1361.720 19.895 1362.620 2389.345 ;
        RECT 1365.020 19.895 1384.320 2389.345 ;
        RECT 1386.720 19.895 1387.620 2389.345 ;
        RECT 1390.020 19.895 1409.320 2389.345 ;
        RECT 1411.720 19.895 1412.620 2389.345 ;
        RECT 1415.020 19.895 1434.320 2389.345 ;
        RECT 1436.720 19.895 1437.620 2389.345 ;
        RECT 1440.020 19.895 1459.320 2389.345 ;
        RECT 1461.720 19.895 1462.620 2389.345 ;
        RECT 1465.020 19.895 1484.320 2389.345 ;
        RECT 1486.720 19.895 1487.620 2389.345 ;
        RECT 1490.020 19.895 1509.320 2389.345 ;
        RECT 1511.720 19.895 1512.620 2389.345 ;
        RECT 1515.020 19.895 1534.320 2389.345 ;
        RECT 1536.720 19.895 1537.620 2389.345 ;
        RECT 1540.020 19.895 1559.320 2389.345 ;
        RECT 1561.720 19.895 1562.620 2389.345 ;
        RECT 1565.020 19.895 1584.320 2389.345 ;
        RECT 1586.720 19.895 1587.620 2389.345 ;
        RECT 1590.020 19.895 1609.320 2389.345 ;
        RECT 1611.720 19.895 1612.620 2389.345 ;
        RECT 1615.020 19.895 1634.320 2389.345 ;
        RECT 1636.720 19.895 1637.620 2389.345 ;
        RECT 1640.020 19.895 1659.320 2389.345 ;
        RECT 1661.720 19.895 1662.620 2389.345 ;
        RECT 1665.020 19.895 1684.320 2389.345 ;
        RECT 1686.720 19.895 1687.620 2389.345 ;
        RECT 1690.020 19.895 1709.320 2389.345 ;
        RECT 1711.720 19.895 1712.620 2389.345 ;
        RECT 1715.020 19.895 1734.320 2389.345 ;
        RECT 1736.720 19.895 1737.620 2389.345 ;
        RECT 1740.020 19.895 1759.320 2389.345 ;
        RECT 1761.720 19.895 1762.620 2389.345 ;
        RECT 1765.020 19.895 1784.320 2389.345 ;
        RECT 1786.720 19.895 1787.620 2389.345 ;
        RECT 1790.020 19.895 1809.320 2389.345 ;
        RECT 1811.720 19.895 1812.620 2389.345 ;
        RECT 1815.020 19.895 1834.320 2389.345 ;
        RECT 1836.720 19.895 1837.620 2389.345 ;
        RECT 1840.020 19.895 1859.320 2389.345 ;
        RECT 1861.720 19.895 1862.620 2389.345 ;
        RECT 1865.020 19.895 1884.320 2389.345 ;
        RECT 1886.720 19.895 1887.620 2389.345 ;
        RECT 1890.020 19.895 1909.320 2389.345 ;
        RECT 1911.720 19.895 1912.620 2389.345 ;
        RECT 1915.020 19.895 1934.320 2389.345 ;
        RECT 1936.720 19.895 1937.620 2389.345 ;
        RECT 1940.020 19.895 1959.320 2389.345 ;
        RECT 1961.720 19.895 1962.620 2389.345 ;
        RECT 1965.020 19.895 1984.320 2389.345 ;
        RECT 1986.720 19.895 1987.620 2389.345 ;
        RECT 1990.020 19.895 2009.320 2389.345 ;
        RECT 2011.720 19.895 2012.620 2389.345 ;
        RECT 2015.020 19.895 2034.320 2389.345 ;
        RECT 2036.720 19.895 2037.620 2389.345 ;
        RECT 2040.020 19.895 2059.320 2389.345 ;
        RECT 2061.720 19.895 2062.620 2389.345 ;
        RECT 2065.020 19.895 2084.320 2389.345 ;
        RECT 2086.720 19.895 2087.620 2389.345 ;
        RECT 2090.020 19.895 2109.320 2389.345 ;
        RECT 2111.720 19.895 2112.620 2389.345 ;
        RECT 2115.020 19.895 2134.320 2389.345 ;
        RECT 2136.720 19.895 2137.620 2389.345 ;
        RECT 2140.020 19.895 2159.320 2389.345 ;
        RECT 2161.720 19.895 2162.620 2389.345 ;
        RECT 2165.020 19.895 2184.320 2389.345 ;
        RECT 2186.720 19.895 2187.620 2389.345 ;
        RECT 2190.020 19.895 2209.320 2389.345 ;
        RECT 2211.720 19.895 2212.620 2389.345 ;
        RECT 2215.020 19.895 2234.320 2389.345 ;
        RECT 2236.720 19.895 2237.620 2389.345 ;
        RECT 2240.020 19.895 2259.320 2389.345 ;
        RECT 2261.720 19.895 2262.620 2389.345 ;
        RECT 2265.020 19.895 2284.320 2389.345 ;
        RECT 2286.720 19.895 2287.620 2389.345 ;
        RECT 2290.020 19.895 2309.320 2389.345 ;
        RECT 2311.720 19.895 2312.620 2389.345 ;
        RECT 2315.020 19.895 2334.320 2389.345 ;
        RECT 2336.720 19.895 2337.620 2389.345 ;
        RECT 2340.020 19.895 2359.320 2389.345 ;
        RECT 2361.720 19.895 2362.620 2389.345 ;
        RECT 2365.020 19.895 2377.905 2389.345 ;
      LAYER met5 ;
        RECT 1326.300 1510.500 1417.140 1512.100 ;
  END
END register_file
END LIBRARY

